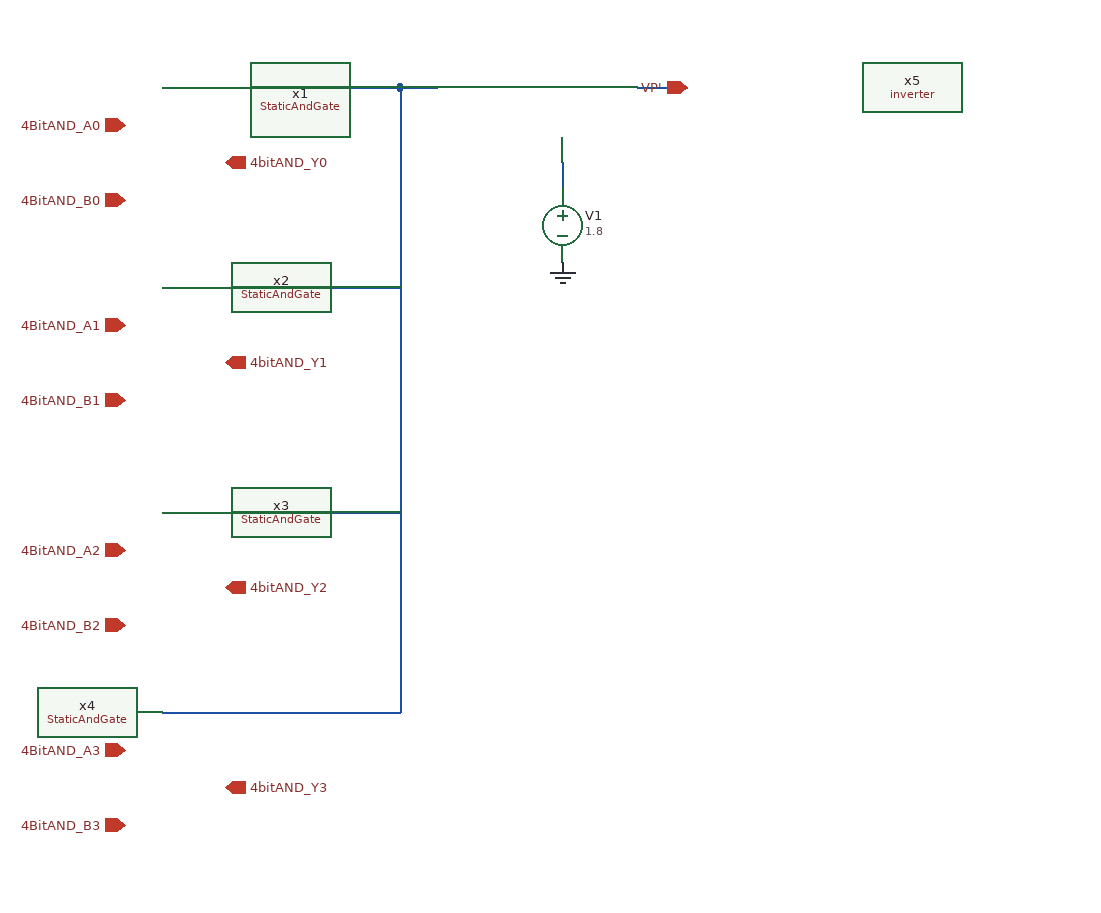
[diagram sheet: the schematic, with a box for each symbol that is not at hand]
v {xschem version=3.4.8RC file_version=1.2}
G {}
K {}
V {}
S {}
E {}
N -30 -120 160 -120 {lab=#net1}
N -30 40 160 40 {lab=#net1}
N 160 -120 160 370 {lab=#net1}
N -30 380 160 380 {lab=#net1}
N 160 370 160 380 {lab=#net1}
N -30 220 160 220 {lab=#net1}
N 350 -120 390 -120 {lab=VP'}
N 160 -120 190 -120 {lab=#net1}
N 290 -60 290 -40 {lab=#net2}
C {ipin.sym} -60 -90 0 0 {name=p1 lab=4BitAND_A0}
C {ipin.sym} -60 70 0 0 {name=p2 lab=4BitAND_A1}
C {ipin.sym} -60 250 0 0 {name=p3 lab=4BitAND_A2}
C {ipin.sym} -60 410 0 0 {name=p4 lab=4BitAND_A3}
C {ipin.sym} -60 470 0 0 {name=p5 lab=4BitAND_B3}
C {ipin.sym} -60 310 0 0 {name=p6 lab=4BitAND_B2}
C {ipin.sym} -60 130 0 0 {name=p7 lab=4BitAND_B1}
C {ipin.sym} -60 -30 0 0 {name=p8 lab=4BitAND_B0}
C {opin.sym} 20 -60 0 0 {name=p9 lab=4bitAND_Y0}
C {opin.sym} 20 100 0 0 {name=p10 lab=4bitAND_Y1}
C {opin.sym} 20 280 0 0 {name=p11 lab=4bitAND_Y2}
C {opin.sym} 20 440 0 0 {name=p12 lab=4bitAND_Y3}
C {iopin.sym} 390 -120 0 0 {name=p13 lab=VP'}
C {/home/safal/projects/trial/inverter.sym} 570 -120 2 0 {name=x5}
C {vsource.sym} 290 -10 0 0 {name=V1 value=1.8 savecurrent=false}
C {gnd.sym} 290 20 0 0 {name=l1 lab=GND}
C {/home/safal/projects/GitHub_CMOS_4bit_ALU/AllSymbols&Sch/Gates/StaticAndGate.sym} 270 -60 0 0 {name=x1}
C {/home/safal/projects/GitHub_CMOS_4bit_ALU/AllSymbols&Sch/Gates/StaticAndGate.sym} 270 100 0 0 {name=x2}
C {/home/safal/projects/GitHub_CMOS_4bit_ALU/AllSymbols&Sch/Gates/StaticAndGate.sym} 270 280 0 0 {name=x3}
C {/home/safal/projects/GitHub_CMOS_4bit_ALU/AllSymbols&Sch/Gates/StaticAndGate.sym} 270 440 0 0 {name=x4}
